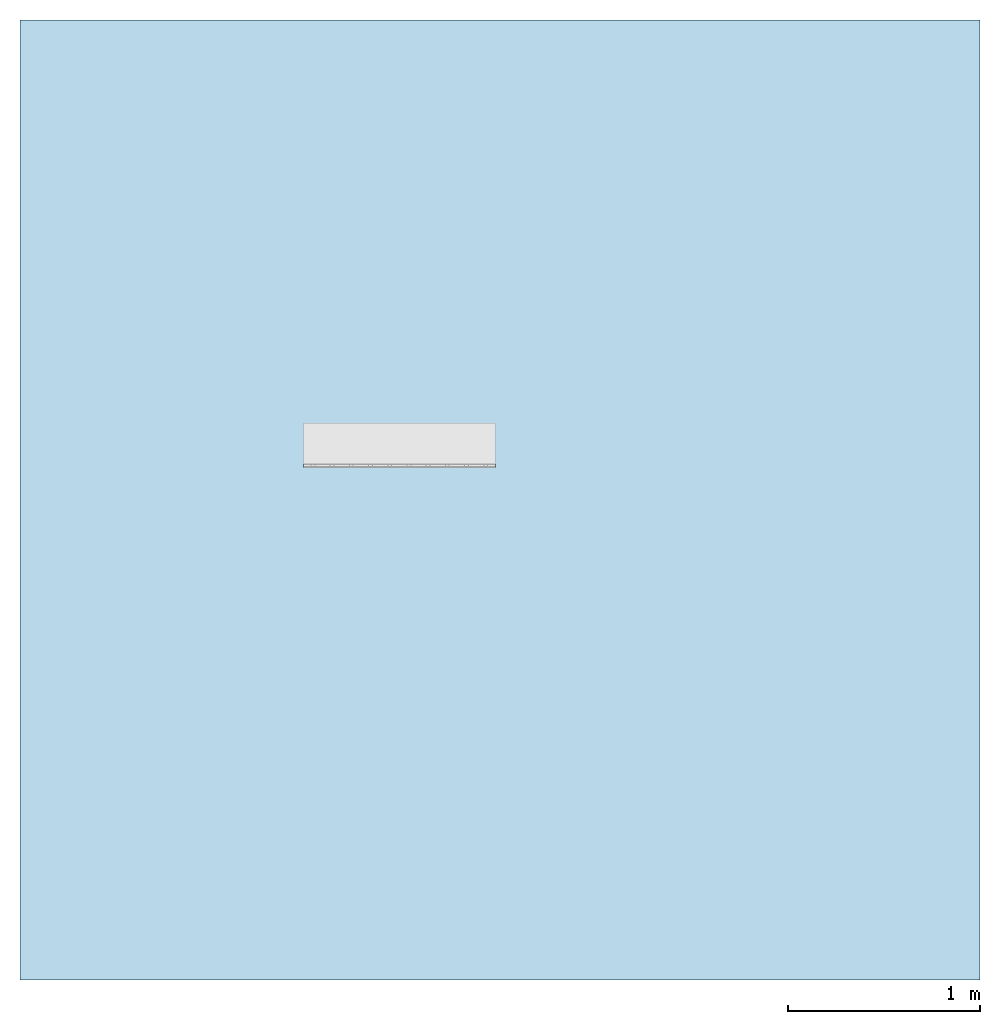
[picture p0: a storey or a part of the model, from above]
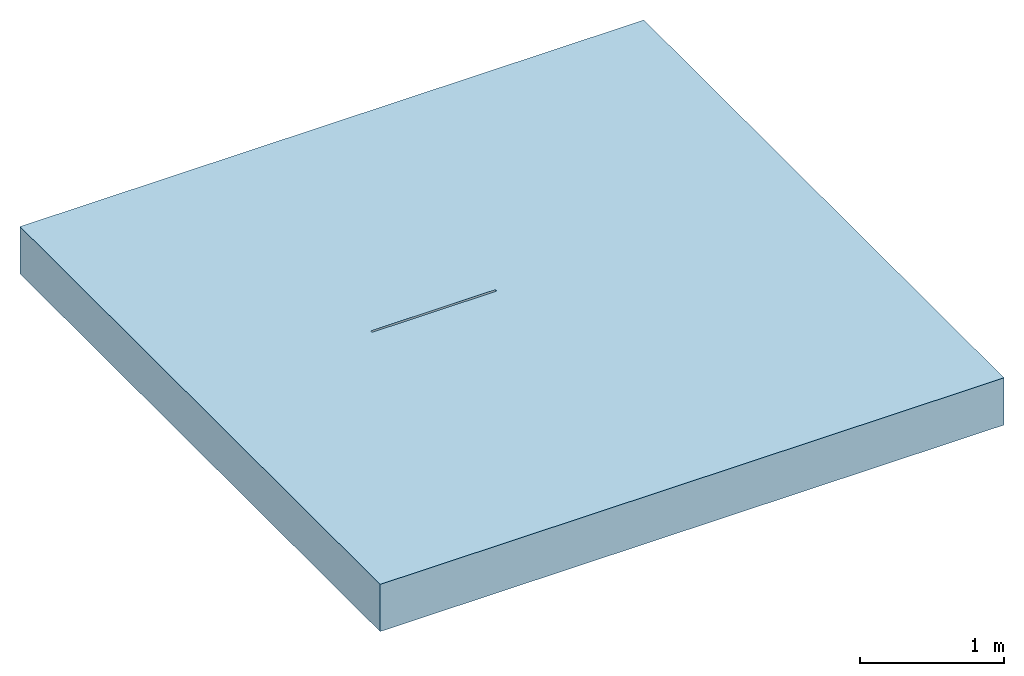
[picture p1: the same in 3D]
Properties of the parts of a building model (IFC2X3)

# File
Description: ViewDefinition [CoordinationView]
File name: 24216 - No 0100 Shallow Depth Channel - 1000mm LG - Invert Depth 75mm.ifc
Time: 2013-10-30T14:14:16
Written by: Autodesk Revit 2013
Made in: 20120221_2030(x64)

# IfcProject, Project Number
LongName: Project Name; Phase: Project Status

# IfcSite, Default
RefLatitude: 42, 21, 30, 344238; RefLongitude: -71, -3, -35, -194702; RefElevation: 0 mm

# IfcBuilding
Pset_BuildingCommon - NumberOfStoreys: 1
Other - Project Status: Project Status; Client Name: Owner; Project Issue Date: Issue Date; Project Address: ## Street City, State Zip; Project Number: Project Number; Project Name: Project Name

# IfcBuildingStorey, Level 1
LongName: Level 1; Elevation: 0 mm
Constraints - Elevation Base: 0; Elevation: 0 mm
Graphics - Line Pattern: Center; Symbol: M_Level Head - Circle: M_Level Head - Circle; Color: 0; Symbol at End 2 Default: yes; Line Weight: 1; Symbol at End 1 Default: no
Identity Data - Structural: no; Name: Level 1; Building Story: yes
Dimensions - Computation Height: 0 mm

# IfcBuildingElementProxy: 24216 - No 0100 Shallow Depth Channel - 1000mm LG - Invert Depth 75mm, Civil-Drainage-Channel-ACO-MultiDrain-M200DS-Brickslot-Channel-System:24216 - No 0100 Shallow Depth Channel - 1000mm LG - Invert Depth 75mm:24216 - No 0100 Shallow Depth Channel - 1000mm LG - Invert Depth 75mm:196059
In: Level 1
Material: Stainless Steel (F), Vienite® Synthetic Resin Concrete
Dimensions - FloorCut_Length: -1000 mm; Length: 1000 mm; Brickslot Access Unit Void Depth: 6000 mm; Brickslot Grating Void Depth: 0 mm; EndCap Position: 1000 mm; Volume: 9199297 mm3; Brickslot Void Length: -1000 mm; Custom_Void_Length: 0 mm; Brickslot Access Unit Void Bottom Depth: 6105 mm; EndCap_Height: 100 mm; Depth: 365 mm; FloorCut_Width: 235 mm; Length Drain: -1000 mm; InvDepth: 240 mm; FloorCut_Depth: 100 mm; FloorCut_HorPosition: 117.5 mm
Construction - 408999_Load Class C250 & D400_Brickslot Grating_Stainless Steel_500mm Long: no; 23219 - Universal Endcap (Male End): no; 23219 - Universal Endcap (Female End): no; 408998_Load Class C250 & D400_Brickslot Grating_Stainless Steel_1000mm Long: yes; 409000_Load Class C250 & D400_Brickslot_Access Unit_Stainless Steel_500mm Long: no; Constant Depth Channel_500: no; Shallow Depth Channel with seal: no; Constant Depth Channel_1000: no; 23410_Sump Unit: no; Shallow Depth Channel: yes
Phasing - Phase Created: New Construction
Constraints - Level: Level: Level 1; Moves With Nearby Elements: no
Pset_BuildingElementProxyCommon - Reference: 24216 - No 0100 Shallow Depth Channel - 1000mm LG - Invert Depth 75mm
Data - ACO Hydraulic Design Software: http://www.acodesign.co.uk; Concrete Surround Volume - Load Class B 125 - C 250 - Concrete Pavement: 0.11m³/m; Load Class: A 15 - D 400; Concrete Surround Volume - Load Class A 15 - Concrete Pavement: 0.06m³/m; Product Dimensions: 1000mm x 235mm x 100mm (LxWxH); Hydraulic Performance: http://www.aco.co.uk/download.php?id=173; Invert Depth: 75mm; Product Standard: BS EN 1433:2002, CE marked; Concrete Surround Volume - Load Class D 400 - Concrete Pavement: 0.17m³/m; Installation - Concrete Grade: Refer to brochure; Product Weight: 19.4 Kg; Channel C.S.A: 0.01m²
Model Properties - Brickslot Grating Product code 408998: Load Class C250/D400 - Brickslot Stainless Steel - 1000mm long x 105mm high - 10mm Slot - Intake area 10000mm²/m - 9.8kg; Brickslot Access Unit Product code 409000: Load Class C250/D400 - Brickslot Access Unit Stainless Steel - 500mm long x 105mm high - 10mm Slot - Intake area 10000mm²/m - 8.5 Kg; Brickslot Grating Product code 408999: Load Class C250/D400 - Brickslot Stainless Steel - 500mm long x 105mm high - 10mm Slot - Intake area 10000mm²/m - 4.8kg; End Cap Product code 23219: No 306 Universal End Cap - 235mm wide x 365mm long - Spigot Ø160mm x 75mm long - Silver - Polypropylene - 0.4kg
Identity Data - Manufacturer: ACO Technologies plc - ACO Water Management Division; OmniClass Title: Rainwater Removal; Assembly Code: D2040; Type Comments: ACO MultiDrain M200DS 0100 Shallow Constant Depth Channel 1000mm Long; Maintenance guidelines: http://www.aco.co.uk/download.php?id=173; Telephone: +44 (0)1462 816666; Product brochure: http://www.aco.co.uk/download.php?id=173; e-mail Sales: customersupport@aco.co.uk; Watermark 2: This file is water marked and users are prohibited to reproduce, adapt, distribute this information; URL: www.aco.co.uk; Installation guidelines: http://www.aco.co.uk/download.php?id=173; Model: ACO MultiDrain MDS Brickslot - M200DS; Product Page URL: http://www.aco.co.uk/product_detail.php?id=58; e-mail Technical: technical@aco.co.uk; Watermark 1: This file is the property of ACO Technologies PLC; Model Description: Channel drainage system; Watermarked By: www.aco.co.uk; Assembly Description: Rain Water Drainage; Product Code: 24216; Price: POA - contact ACO; Fax: +44 (0)1462 815895; OmniClass Number: 23.70.50.24; Cost: 0; Watermarked With: BIM Manager Premium Suite; Address: ACO Business Park, Hitchin Road, Shefford, Bedfordshire, United Kingdom SG17 5TE
General - SerialNumber: 0; TagNumber: 0
Green Building Properties - Edge Rail Recyclable: Fully recyclable; Channel Recyclable: Fully recyclable; Edge Rail Recycled Material Content: Between 40% - 90%; Channel Recycled Material Content: 20% minimum
Other - Revision: 1; CreatedBy: www.aco.co.uk
Materials and Finishes - Channel Colour: Brown; Edge Rail Colour: Self; Channel Material: Vienite® Synthetic Resin Concrete; Edge Rail Material: Stainless Steel Grade 304

# IfcOpeningElement: Recess (2)
In: Level 1
Constraints - Height Offset From Level: 0 mm; Related to Mass: no; Level: Level: Level 1; Room Bounding: yes
Structural - Structural: no; Enable Analytical Model: no
Dimensions - Area: 25000000 mm2; Thickness: 400 mm; Perimeter: 20000 mm; Volume: 9974610000 mm3
Phasing - Phase Created: New Construction
Construction - Function: 0; Default Thickness: 400 mm
Analytical Properties - Heat Transfer Coefficient (U): 2.0925; Roughness: 1; Thermal mass: 543920; Absorptance: 0.1; Thermal Resistance (R): 0.477897
Materials and Finishes - Structural Material: Earth
Graphics - Coarse Scale Fill Color: 0

# IfcSlab: Floor:Generic Floor - 400mm, Floor:Generic Floor - 400mm:193825
In: Level 1
PredefinedType: FLOOR; Material: Earth 400 mm
Constraints - Height Offset From Level: 0 mm; Related to Mass: no; Level: Level: Level 1; Room Bounding: yes
Structural - Structural: no; Enable Analytical Model: no
Dimensions - Area: 25000000 mm2; Thickness: 400 mm; Perimeter: 20000 mm; Volume: 9974610000 mm3
Phasing - Phase Created: New Construction
Pset_SlabCommon - Reference: Generic Floor - 400mm; IsExternal: no; LoadBearing: yes
Construction - Function: 0; Default Thickness: 400 mm
Analytical Properties - Heat Transfer Coefficient (U): 2.0925; Roughness: 1; Thermal mass: 543920; Absorptance: 0.1; Thermal Resistance (R): 0.477897
Materials and Finishes - Structural Material: Earth
Graphics - Coarse Scale Fill Color: 0
